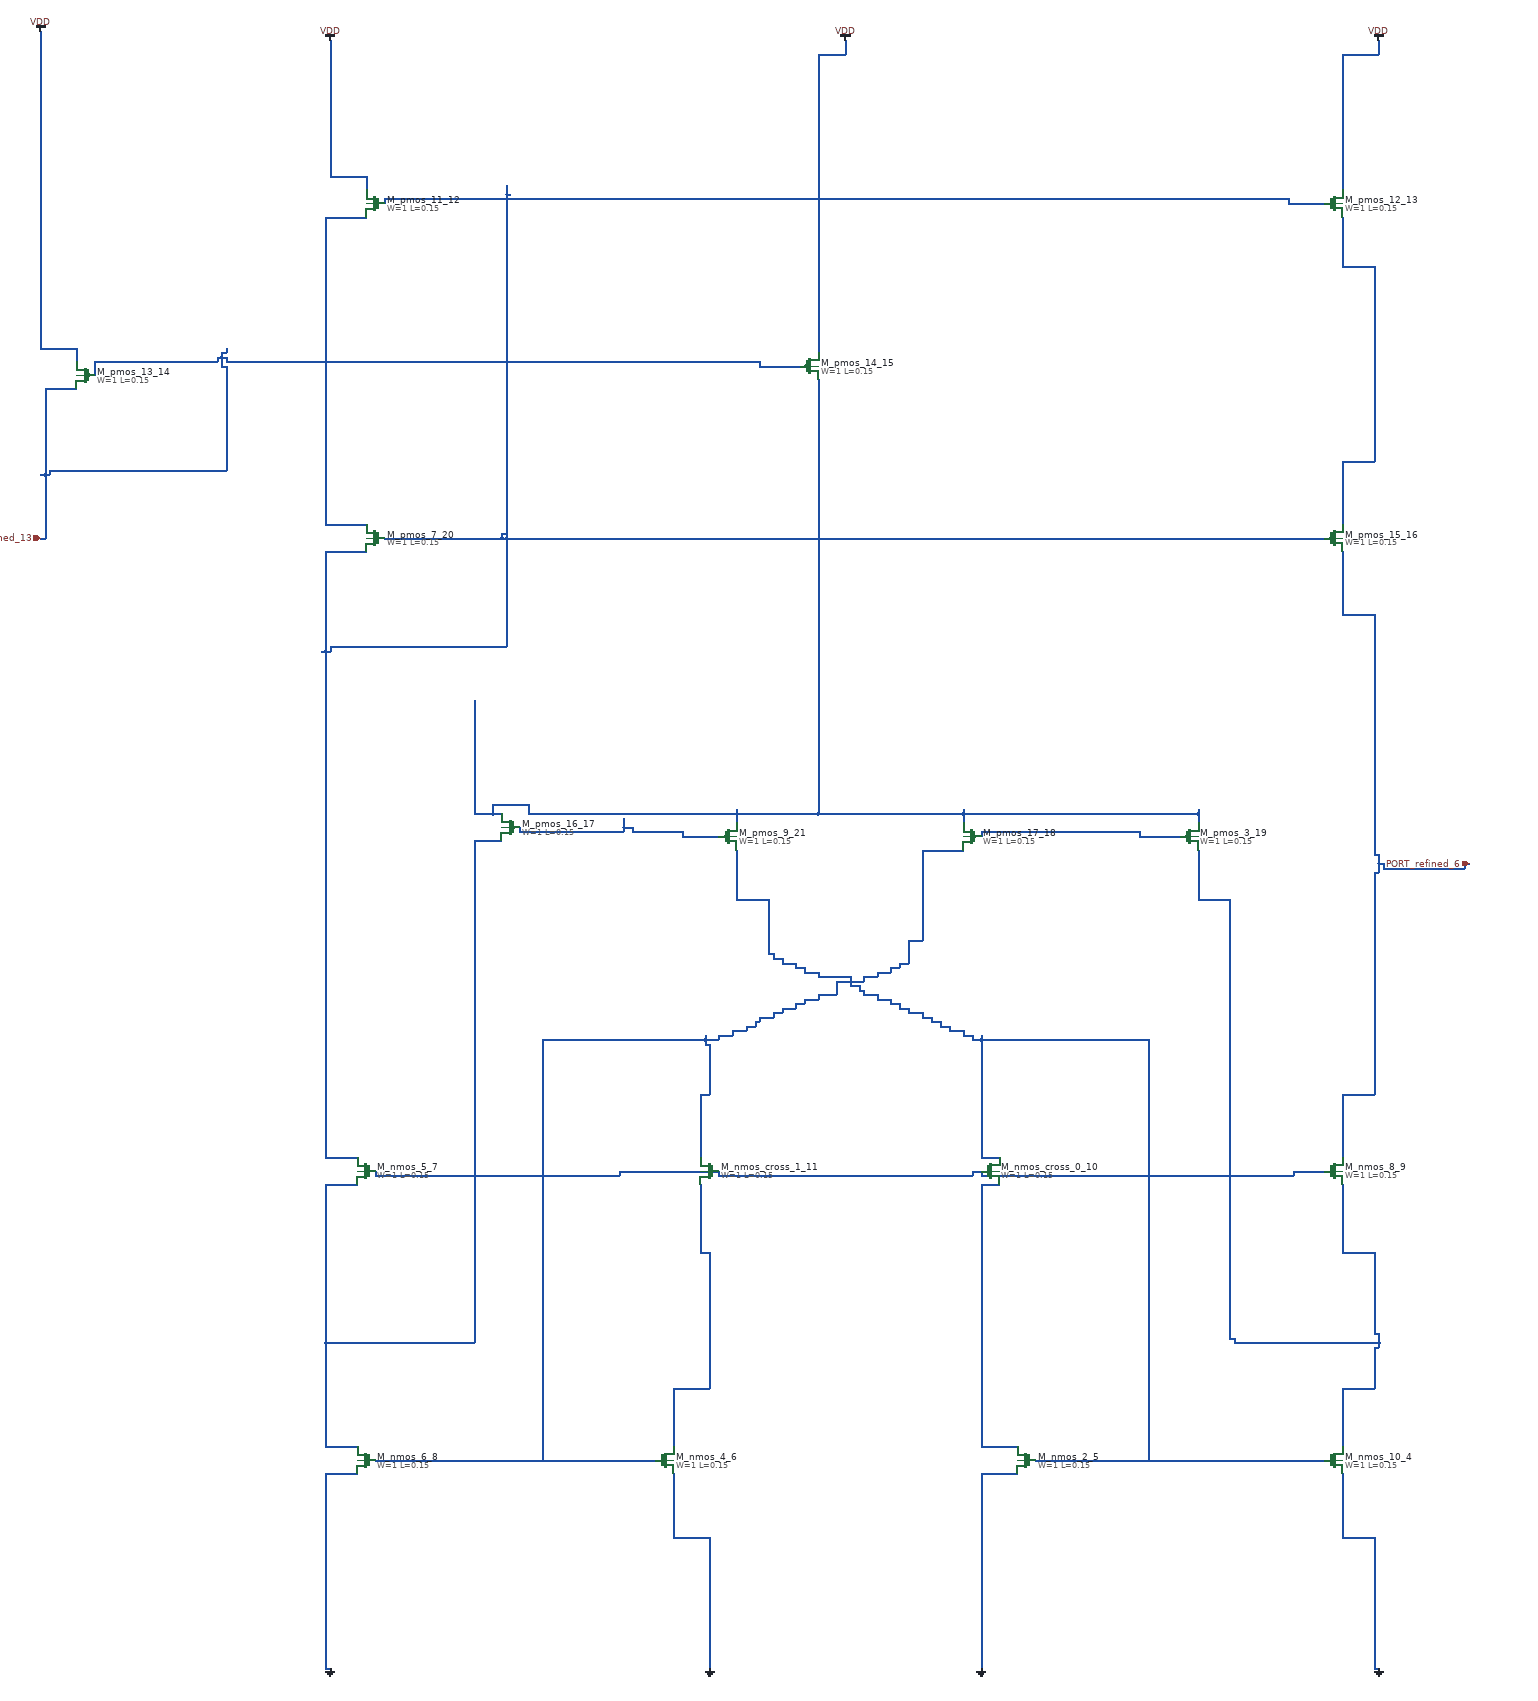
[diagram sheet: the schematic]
v {xschem version=3.4.8 file_version=1.2}
G {}
K {}
V {}
S {}
E {}
C {devices/gnd.sym} 840 3680 0 0 {name="l_gnd_18_0" lab="GND"}
C {devices/gnd.sym} 2280 3680 0 0 {name="l_gnd_19_1" lab="GND"}
C {devices/gnd.sym} 3160 3680 0 0 {name="l_gnd_20_2" lab="GND"}
C {devices/gnd.sym} 1680 3680 0 0 {name="l_gnd_21_3" lab="GND"}
C {sky130_fd_pr/nfet3_01v8.sym} 3060 3220 0 0 {name="M_nmos_10_4"
W=1
L=0.15
body=GND
nf=1
mult=1
ad="expr('int((@nf + 1)/2) * @W / @nf * 0.29')"
pd="expr('2*int((@nf + 1)/2) * (@W / @nf + 0.29)')"
as="expr('int((@nf + 2)/2) * @W / @nf * 0.29')"
ps="expr('2*int((@nf + 2)/2) * (@W / @nf + 0.29)')"
nrd="expr('0.29 / @W ')" nrs="expr('0.29 / @W ')"
sa=0 sb=0 sd=0
model=nfet_01v8
spiceprefix=X
}
C {sky130_fd_pr/nfet3_01v8.sym} 2380 3220 0 1 {name="M_nmos_2_5"
W=1
L=0.15
body=GND
nf=1
mult=1
ad="expr('int((@nf + 1)/2) * @W / @nf * 0.29')"
pd="expr('2*int((@nf + 1)/2) * (@W / @nf + 0.29)')"
as="expr('int((@nf + 2)/2) * @W / @nf * 0.29')"
ps="expr('2*int((@nf + 2)/2) * (@W / @nf + 0.29)')"
nrd="expr('0.29 / @W ')" nrs="expr('0.29 / @W ')"
sa=0 sb=0 sd=0
model=nfet_01v8
spiceprefix=X
}
C {sky130_fd_pr/nfet3_01v8.sym} 1580 3220 0 0 {name="M_nmos_4_6"
W=1
L=0.15
body=GND
nf=1
mult=1
ad="expr('int((@nf + 1)/2) * @W / @nf * 0.29')"
pd="expr('2*int((@nf + 1)/2) * (@W / @nf + 0.29)')"
as="expr('int((@nf + 2)/2) * @W / @nf * 0.29')"
ps="expr('2*int((@nf + 2)/2) * (@W / @nf + 0.29)')"
nrd="expr('0.29 / @W ')" nrs="expr('0.29 / @W ')"
sa=0 sb=0 sd=0
model=nfet_01v8
spiceprefix=X
}
C {sky130_fd_pr/nfet3_01v8.sym} 920 2580 0 1 {name="M_nmos_5_7"
W=1
L=0.15
body=GND
nf=1
mult=1
ad="expr('int((@nf + 1)/2) * @W / @nf * 0.29')"
pd="expr('2*int((@nf + 1)/2) * (@W / @nf + 0.29)')"
as="expr('int((@nf + 2)/2) * @W / @nf * 0.29')"
ps="expr('2*int((@nf + 2)/2) * (@W / @nf + 0.29)')"
nrd="expr('0.29 / @W ')" nrs="expr('0.29 / @W ')"
sa=0 sb=0 sd=0
model=nfet_01v8
spiceprefix=X
}
C {sky130_fd_pr/nfet3_01v8.sym} 920 3220 0 1 {name="M_nmos_6_8"
W=1
L=0.15
body=GND
nf=1
mult=1
ad="expr('int((@nf + 1)/2) * @W / @nf * 0.29')"
pd="expr('2*int((@nf + 1)/2) * (@W / @nf + 0.29)')"
as="expr('int((@nf + 2)/2) * @W / @nf * 0.29')"
ps="expr('2*int((@nf + 2)/2) * (@W / @nf + 0.29)')"
nrd="expr('0.29 / @W ')" nrs="expr('0.29 / @W ')"
sa=0 sb=0 sd=0
model=nfet_01v8
spiceprefix=X
}
C {sky130_fd_pr/nfet3_01v8.sym} 3060 2580 0 0 {name="M_nmos_8_9"
W=1
L=0.15
body=GND
nf=1
mult=1
ad="expr('int((@nf + 1)/2) * @W / @nf * 0.29')"
pd="expr('2*int((@nf + 1)/2) * (@W / @nf + 0.29)')"
as="expr('int((@nf + 2)/2) * @W / @nf * 0.29')"
ps="expr('2*int((@nf + 2)/2) * (@W / @nf + 0.29)')"
nrd="expr('0.29 / @W ')" nrs="expr('0.29 / @W ')"
sa=0 sb=0 sd=0
model=nfet_01v8
spiceprefix=X
}
C {sky130_fd_pr/nfet3_01v8.sym} 2300 2580 0 0 {name="M_nmos_cross_0_10"
W=1
L=0.15
body=GND
nf=1
mult=1
ad="expr('int((@nf + 1)/2) * @W / @nf * 0.29')"
pd="expr('2*int((@nf + 1)/2) * (@W / @nf + 0.29)')"
as="expr('int((@nf + 2)/2) * @W / @nf * 0.29')"
ps="expr('2*int((@nf + 2)/2) * (@W / @nf + 0.29)')"
nrd="expr('0.29 / @W ')" nrs="expr('0.29 / @W ')"
sa=0 sb=0 sd=0
model=nfet_01v8
spiceprefix=X
}
C {sky130_fd_pr/nfet3_01v8.sym} 1680 2580 0 1 {name="M_nmos_cross_1_11"
W=1
L=0.15
body=GND
nf=1
mult=1
ad="expr('int((@nf + 1)/2) * @W / @nf * 0.29')"
pd="expr('2*int((@nf + 1)/2) * (@W / @nf + 0.29)')"
as="expr('int((@nf + 2)/2) * @W / @nf * 0.29')"
ps="expr('2*int((@nf + 2)/2) * (@W / @nf + 0.29)')"
nrd="expr('0.29 / @W ')" nrs="expr('0.29 / @W ')"
sa=0 sb=0 sd=0
model=nfet_01v8
spiceprefix=X
}
C {sky130_fd_pr/pfet3_01v8.sym} 940 440 0 1 {name="M_pmos_11_12"
W=1
L=0.15
body=VDD
nf=1
mult=1
ad="expr('int((@nf + 1)/2) * @W / @nf * 0.29')"
pd="expr('2*int((@nf + 1)/2) * (@W / @nf + 0.29)')"
as="expr('int((@nf + 2)/2) * @W / @nf * 0.29')"
ps="expr('2*int((@nf + 2)/2) * (@W / @nf + 0.29)')"
nrd="expr('0.29 / @W ')" nrs="expr('0.29 / @W ')"
sa=0 sb=0 sd=0
model=pfet_01v8
spiceprefix=X
}
C {sky130_fd_pr/pfet3_01v8.sym} 3060 440 0 0 {name="M_pmos_12_13"
W=1
L=0.15
body=VDD
nf=1
mult=1
ad="expr('int((@nf + 1)/2) * @W / @nf * 0.29')"
pd="expr('2*int((@nf + 1)/2) * (@W / @nf + 0.29)')"
as="expr('int((@nf + 2)/2) * @W / @nf * 0.29')"
ps="expr('2*int((@nf + 2)/2) * (@W / @nf + 0.29)')"
nrd="expr('0.29 / @W ')" nrs="expr('0.29 / @W ')"
sa=0 sb=0 sd=0
model=pfet_01v8
spiceprefix=X
}
C {sky130_fd_pr/pfet3_01v8.sym} 300 820 0 1 {name="M_pmos_13_14"
W=1
L=0.15
body=VDD
nf=1
mult=1
ad="expr('int((@nf + 1)/2) * @W / @nf * 0.29')"
pd="expr('2*int((@nf + 1)/2) * (@W / @nf + 0.29)')"
as="expr('int((@nf + 2)/2) * @W / @nf * 0.29')"
ps="expr('2*int((@nf + 2)/2) * (@W / @nf + 0.29)')"
nrd="expr('0.29 / @W ')" nrs="expr('0.29 / @W ')"
sa=0 sb=0 sd=0
model=pfet_01v8
spiceprefix=X
}
C {sky130_fd_pr/pfet3_01v8.sym} 1900 800 0 0 {name="M_pmos_14_15"
W=1
L=0.15
body=VDD
nf=1
mult=1
ad="expr('int((@nf + 1)/2) * @W / @nf * 0.29')"
pd="expr('2*int((@nf + 1)/2) * (@W / @nf + 0.29)')"
as="expr('int((@nf + 2)/2) * @W / @nf * 0.29')"
ps="expr('2*int((@nf + 2)/2) * (@W / @nf + 0.29)')"
nrd="expr('0.29 / @W ')" nrs="expr('0.29 / @W ')"
sa=0 sb=0 sd=0
model=pfet_01v8
spiceprefix=X
}
C {sky130_fd_pr/pfet3_01v8.sym} 3060 1180 0 0 {name="M_pmos_15_16"
W=1
L=0.15
body=VDD
nf=1
mult=1
ad="expr('int((@nf + 1)/2) * @W / @nf * 0.29')"
pd="expr('2*int((@nf + 1)/2) * (@W / @nf + 0.29)')"
as="expr('int((@nf + 2)/2) * @W / @nf * 0.29')"
ps="expr('2*int((@nf + 2)/2) * (@W / @nf + 0.29)')"
nrd="expr('0.29 / @W ')" nrs="expr('0.29 / @W ')"
sa=0 sb=0 sd=0
model=pfet_01v8
spiceprefix=X
}
C {sky130_fd_pr/pfet3_01v8.sym} 1240 1820 0 1 {name="M_pmos_16_17"
W=1
L=0.15
body=VDD
nf=1
mult=1
ad="expr('int((@nf + 1)/2) * @W / @nf * 0.29')"
pd="expr('2*int((@nf + 1)/2) * (@W / @nf + 0.29)')"
as="expr('int((@nf + 2)/2) * @W / @nf * 0.29')"
ps="expr('2*int((@nf + 2)/2) * (@W / @nf + 0.29)')"
nrd="expr('0.29 / @W ')" nrs="expr('0.29 / @W ')"
sa=0 sb=0 sd=0
model=pfet_01v8
spiceprefix=X
}
C {sky130_fd_pr/pfet3_01v8.sym} 2260 1840 0 1 {name="M_pmos_17_18"
W=1
L=0.15
body=VDD
nf=1
mult=1
ad="expr('int((@nf + 1)/2) * @W / @nf * 0.29')"
pd="expr('2*int((@nf + 1)/2) * (@W / @nf + 0.29)')"
as="expr('int((@nf + 2)/2) * @W / @nf * 0.29')"
ps="expr('2*int((@nf + 2)/2) * (@W / @nf + 0.29)')"
nrd="expr('0.29 / @W ')" nrs="expr('0.29 / @W ')"
sa=0 sb=0 sd=0
model=pfet_01v8
spiceprefix=X
}
C {sky130_fd_pr/pfet3_01v8.sym} 2740 1840 0 0 {name="M_pmos_3_19"
W=1
L=0.15
body=VDD
nf=1
mult=1
ad="expr('int((@nf + 1)/2) * @W / @nf * 0.29')"
pd="expr('2*int((@nf + 1)/2) * (@W / @nf + 0.29)')"
as="expr('int((@nf + 2)/2) * @W / @nf * 0.29')"
ps="expr('2*int((@nf + 2)/2) * (@W / @nf + 0.29)')"
nrd="expr('0.29 / @W ')" nrs="expr('0.29 / @W ')"
sa=0 sb=0 sd=0
model=pfet_01v8
spiceprefix=X
}
C {sky130_fd_pr/pfet3_01v8.sym} 940 1180 0 1 {name="M_pmos_7_20"
W=1
L=0.15
body=VDD
nf=1
mult=1
ad="expr('int((@nf + 1)/2) * @W / @nf * 0.29')"
pd="expr('2*int((@nf + 1)/2) * (@W / @nf + 0.29)')"
as="expr('int((@nf + 2)/2) * @W / @nf * 0.29')"
ps="expr('2*int((@nf + 2)/2) * (@W / @nf + 0.29)')"
nrd="expr('0.29 / @W ')" nrs="expr('0.29 / @W ')"
sa=0 sb=0 sd=0
model=pfet_01v8
spiceprefix=X
}
C {sky130_fd_pr/pfet3_01v8.sym} 1720 1840 0 0 {name="M_pmos_9_21"
W=1
L=0.15
body=VDD
nf=1
mult=1
ad="expr('int((@nf + 1)/2) * @W / @nf * 0.29')"
pd="expr('2*int((@nf + 1)/2) * (@W / @nf + 0.29)')"
as="expr('int((@nf + 2)/2) * @W / @nf * 0.29')"
ps="expr('2*int((@nf + 2)/2) * (@W / @nf + 0.29)')"
nrd="expr('0.29 / @W ')" nrs="expr('0.29 / @W ')"
sa=0 sb=0 sd=0
model=pfet_01v8
spiceprefix=X
}
C {devices/ipin.sym} 3360 1900 0 0 {name="p_port_22_22" lab="PORT_refined_6"}
C {devices/ipin.sym} 200 1180 0 0 {name="p_port_28_23" lab="PORT_refined_13"}
C {devices/vdd.sym} 3160 80 0 0 {name="l_vdd_23_24" lab="VDD"}
C {devices/vdd.sym} 840 80 0 0 {name="l_vdd_24_25" lab="VDD"}
C {devices/vdd.sym} 1980 80 0 0 {name="l_vdd_25_26" lab="VDD"}
C {devices/vdd.sym} 200 60 0 0 {name="l_vdd_26_27" lab="VDD"}
N 830 3680 840 3680 {}
N 3150 3680 3160 3680 {}
N 1600 3390 1680 3390 {}
N 3080 3390 3150 3390 {}
N 830 3250 900 3250 {}
N 2280 3250 2360 3250 {}
N 830 3680 830 3250 {}
N 1600 3390 1600 3250 {}
N 1680 3680 1680 3390 {}
N 2280 3680 2280 3250 {}
N 3080 3390 3080 3250 {}
N 3150 3680 3150 3390 {}
N 1600 3060 1680 3060 {}
N 1660 2760 1680 2760 {}
N 1600 3190 1600 3060 {}
N 1660 2760 1660 2610 {}
N 1680 3060 1680 2760 {}
N 830 1150 920 1150 {}
N 830 470 920 470 {}
N 830 1150 830 470 {}
N 200 760 280 760 {}
N 840 380 920 380 {}
N 1920 110 1980 110 {}
N 3080 110 3160 110 {}
N 200 760 200 60 {}
N 280 790 280 760 {}
N 840 380 840 80 {}
N 920 410 920 380 {}
N 1920 770 1920 110 {}
N 1980 110 1980 80 {}
N 3080 410 3080 110 {}
N 3160 110 3160 80 {}
N 3080 1010 3150 1010 {}
N 3080 580 3150 580 {}
N 3080 1150 3080 1010 {}
N 3080 580 3080 470 {}
N 3150 1010 3150 580 {}
N 200 1180 210 1180 {}
N 200 1040 210 1040 {}
N 210 1040 220 1040 {}
N 220 1030 610 1030 {}
N 210 850 280 850 {}
N 600 800 610 800 {}
N 1790 800 1880 800 {}
N 320 790 590 790 {}
N 610 790 1790 790 {}
N 590 780 600 780 {}
N 600 780 610 780 {}
N 600 770 610 770 {}
N 210 1180 210 1040 {}
N 210 1040 210 850 {}
N 220 1040 220 1030 {}
N 320 820 320 790 {}
N 590 790 590 780 {}
N 600 800 600 780 {}
N 600 780 600 770 {}
N 610 1030 610 800 {}
N 610 790 610 780 {}
N 610 770 610 760 {}
N 1790 800 1790 790 {}
N 1160 1790 1200 1790 {}
N 1200 1790 1220 1790 {}
N 1280 1790 1740 1790 {}
N 1740 1790 1920 1790 {}
N 1920 1790 2240 1790 {}
N 2240 1790 2760 1790 {}
N 1200 1770 1280 1770 {}
N 1160 1790 1160 1540 {}
N 1200 1790 1200 1770 {}
N 1280 1790 1280 1770 {}
N 1740 1810 1740 1790 {}
N 1740 1790 1740 1780 {}
N 1920 1790 1920 830 {}
N 2240 1810 2240 1790 {}
N 2240 1790 2240 1780 {}
N 2760 1810 2760 1790 {}
N 2760 1790 2760 1780 {}
N 1620 1840 1700 1840 {}
N 1260 1830 1490 1830 {}
N 1510 1830 1620 1830 {}
N 1490 1820 1510 1820 {}
N 1260 1830 1260 1820 {}
N 1490 1830 1490 1820 {}
N 1490 1820 1490 1800 {}
N 1510 1830 1510 1820 {}
N 1620 1840 1620 1830 {}
N 2630 1840 2720 1840 {}
N 2280 1830 2630 1830 {}
N 2280 1840 2280 1830 {}
N 2630 1840 2630 1830 {}
N 940 3220 1310 3220 {}
N 1310 3220 1560 3220 {}
N 1660 2410 1680 2410 {}
N 1670 2300 1680 2300 {}
N 1310 2290 1670 2290 {}
N 1670 2290 1700 2290 {}
N 1700 2280 1730 2280 {}
N 1730 2270 1760 2270 {}
N 1760 2260 1780 2260 {}
N 1780 2250 1790 2250 {}
N 1790 2240 1820 2240 {}
N 1820 2230 1840 2230 {}
N 1840 2220 1870 2220 {}
N 1870 2210 1890 2210 {}
N 1890 2200 1920 2200 {}
N 1920 2190 1960 2190 {}
N 1960 2160 2020 2160 {}
N 2020 2150 2050 2150 {}
N 2050 2140 2080 2140 {}
N 2080 2130 2100 2130 {}
N 2100 2120 2120 2120 {}
N 2120 2070 2150 2070 {}
N 2150 1870 2240 1870 {}
N 1310 3220 1310 2290 {}
N 1660 2550 1660 2410 {}
N 1670 2300 1670 2290 {}
N 1670 2290 1670 2280 {}
N 1680 2410 1680 2300 {}
N 1700 2290 1700 2280 {}
N 1730 2280 1730 2270 {}
N 1760 2270 1760 2260 {}
N 1780 2260 1780 2250 {}
N 1790 2250 1790 2240 {}
N 1820 2240 1820 2230 {}
N 1840 2230 1840 2220 {}
N 1870 2220 1870 2210 {}
N 1890 2210 1890 2200 {}
N 1920 2200 1920 2190 {}
N 1960 2190 1960 2160 {}
N 2020 2160 2020 2150 {}
N 2050 2150 2050 2140 {}
N 2080 2140 2080 2130 {}
N 2100 2130 2100 2120 {}
N 2120 2120 2120 2070 {}
N 2150 2070 2150 1870 {}
N 830 3190 900 3190 {}
N 830 2960 1160 2960 {}
N 830 2610 900 2610 {}
N 1160 1850 1220 1850 {}
N 830 3190 830 2960 {}
N 830 2960 830 2610 {}
N 1160 2960 1160 1850 {}
N 830 2550 900 2550 {}
N 820 1430 830 1430 {}
N 830 1430 840 1430 {}
N 840 1420 1230 1420 {}
N 830 1210 920 1210 {}
N 960 1180 1220 1180 {}
N 1220 1180 1230 1180 {}
N 1230 1180 3040 1180 {}
N 1220 1170 1230 1170 {}
N 2960 440 3040 440 {}
N 960 430 1230 430 {}
N 1230 430 2960 430 {}
N 1230 420 1240 420 {}
N 830 2550 830 1430 {}
N 830 1430 830 1210 {}
N 840 1430 840 1420 {}
N 960 440 960 430 {}
N 1220 1180 1220 1170 {}
N 1230 1420 1230 1180 {}
N 1230 1180 1230 1170 {}
N 1230 1170 1230 430 {}
N 1230 430 1230 420 {}
N 1230 420 1230 400 {}
N 2960 440 2960 430 {}
N 940 2590 1480 2590 {}
N 1700 2590 2260 2590 {}
N 2280 2590 2970 2590 {}
N 1480 2580 1700 2580 {}
N 2260 2580 2280 2580 {}
N 2970 2580 3040 2580 {}
N 940 2590 940 2580 {}
N 1480 2590 1480 2580 {}
N 1700 2590 1700 2580 {}
N 2260 2590 2260 2580 {}
N 2280 2590 2280 2580 {}
N 2970 2590 2970 2580 {}
N 3080 2410 3150 2410 {}
N 3150 1920 3160 1920 {}
N 3170 1910 3350 1910 {}
N 3160 1900 3170 1900 {}
N 3350 1900 3360 1900 {}
N 3150 1880 3160 1880 {}
N 3080 1350 3150 1350 {}
N 3080 2550 3080 2410 {}
N 3080 1350 3080 1210 {}
N 3150 2410 3150 1920 {}
N 3150 1880 3150 1350 {}
N 3160 1920 3160 1900 {}
N 3160 1900 3160 1880 {}
N 3170 1910 3170 1900 {}
N 3350 1910 3350 1900 {}
N 3080 3060 3150 3060 {}
N 3150 2970 3160 2970 {}
N 2840 2960 3160 2960 {}
N 2830 2950 2840 2950 {}
N 3150 2940 3160 2940 {}
N 3080 2760 3150 2760 {}
N 2760 1980 2830 1980 {}
N 2760 1980 2760 1870 {}
N 2830 2950 2830 1980 {}
N 2840 2960 2840 2950 {}
N 3080 3190 3080 3060 {}
N 3080 2760 3080 2610 {}
N 3150 3060 3150 2970 {}
N 3150 2940 3150 2760 {}
N 3160 2970 3160 2960 {}
N 3160 2960 3160 2940 {}
N 2280 3190 2360 3190 {}
N 2280 2610 2320 2610 {}
N 2280 3190 2280 2610 {}
N 2400 3220 2650 3220 {}
N 2650 3220 3040 3220 {}
N 2280 2550 2320 2550 {}
N 2260 2290 2280 2290 {}
N 2280 2290 2650 2290 {}
N 2240 2280 2260 2280 {}
N 2210 2270 2240 2270 {}
N 2190 2260 2210 2260 {}
N 2170 2250 2190 2250 {}
N 2150 2240 2170 2240 {}
N 2120 2230 2150 2230 {}
N 2100 2220 2120 2220 {}
N 2080 2210 2100 2210 {}
N 2050 2200 2080 2200 {}
N 2020 2190 2050 2190 {}
N 2010 2180 2020 2180 {}
N 1990 2170 2010 2170 {}
N 1920 2150 1990 2150 {}
N 1890 2140 1920 2140 {}
N 1870 2130 1890 2130 {}
N 1840 2120 1870 2120 {}
N 1820 2110 1840 2110 {}
N 1810 2100 1820 2100 {}
N 1740 1980 1810 1980 {}
N 1740 1980 1740 1870 {}
N 1810 2100 1810 1980 {}
N 1820 2110 1820 2100 {}
N 1840 2120 1840 2110 {}
N 1870 2130 1870 2120 {}
N 1890 2140 1890 2130 {}
N 1920 2150 1920 2140 {}
N 1990 2170 1990 2150 {}
N 2010 2180 2010 2170 {}
N 2020 2190 2020 2180 {}
N 2050 2200 2050 2190 {}
N 2080 2210 2080 2200 {}
N 2100 2220 2100 2210 {}
N 2120 2230 2120 2220 {}
N 2150 2240 2150 2230 {}
N 2170 2250 2170 2240 {}
N 2190 2260 2190 2250 {}
N 2210 2270 2210 2260 {}
N 2240 2280 2240 2270 {}
N 2260 2290 2260 2280 {}
N 2280 2550 2280 2290 {}
N 2280 2290 2280 2280 {}
N 2650 3220 2650 2290 {}
